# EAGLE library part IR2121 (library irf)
Current limiting low side driver

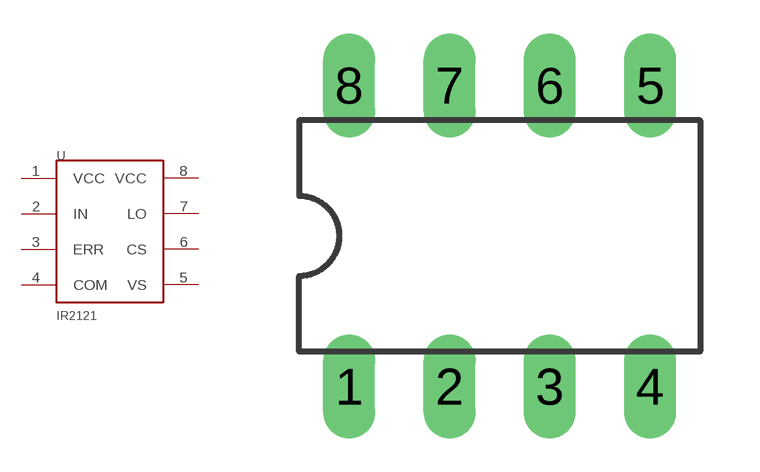
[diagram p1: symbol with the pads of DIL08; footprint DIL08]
Designator prefix U

## IR2121  [DIL08]
1  VCC  sup
2  IN  in
3  ERR  in
4  COM  sup
5  VS  sup
6  CS  in
7  LO  out
8  VCC  sup

## Footprint DIL08 (pad centres in mm)
Dual In Line Package
drill 0.813 long: 1 -3.81,-3.81; 2 -1.27,-3.81; 3 1.27,-3.81; 4 3.81,-3.81; 5 3.81,3.81; 6 1.27,3.81; 7 -1.27,3.81; 8 -3.81,3.81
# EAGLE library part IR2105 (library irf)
Half bridge driver

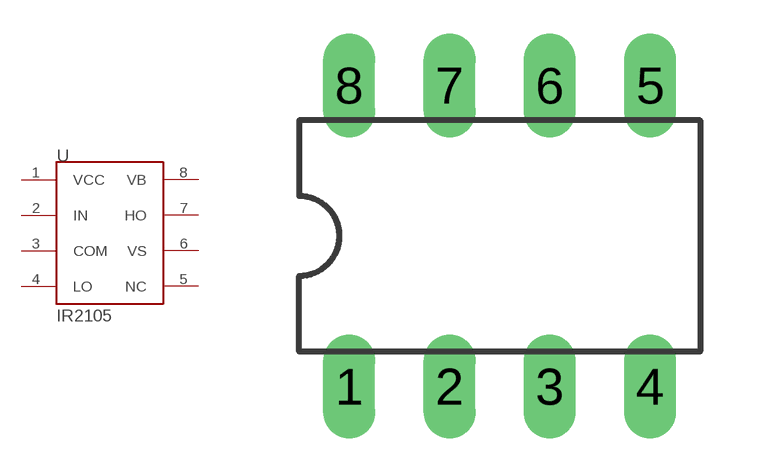
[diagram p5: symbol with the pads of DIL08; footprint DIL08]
Designator prefix U

## IR2105  [DIL08]
1  VCC  sup
2  IN  in
3  COM  sup
4  LO  out
5  NC  nc
6  VS  out
7  HO  out
8  VB  sup

## Footprint DIL08 (pad centres in mm)
Dual In Line Package
drill 0.813 long: 1 -3.81,-3.81; 2 -1.27,-3.81; 3 1.27,-3.81; 4 3.81,-3.81; 5 3.81,3.81; 6 1.27,3.81; 7 -1.27,3.81; 8 -3.81,3.81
